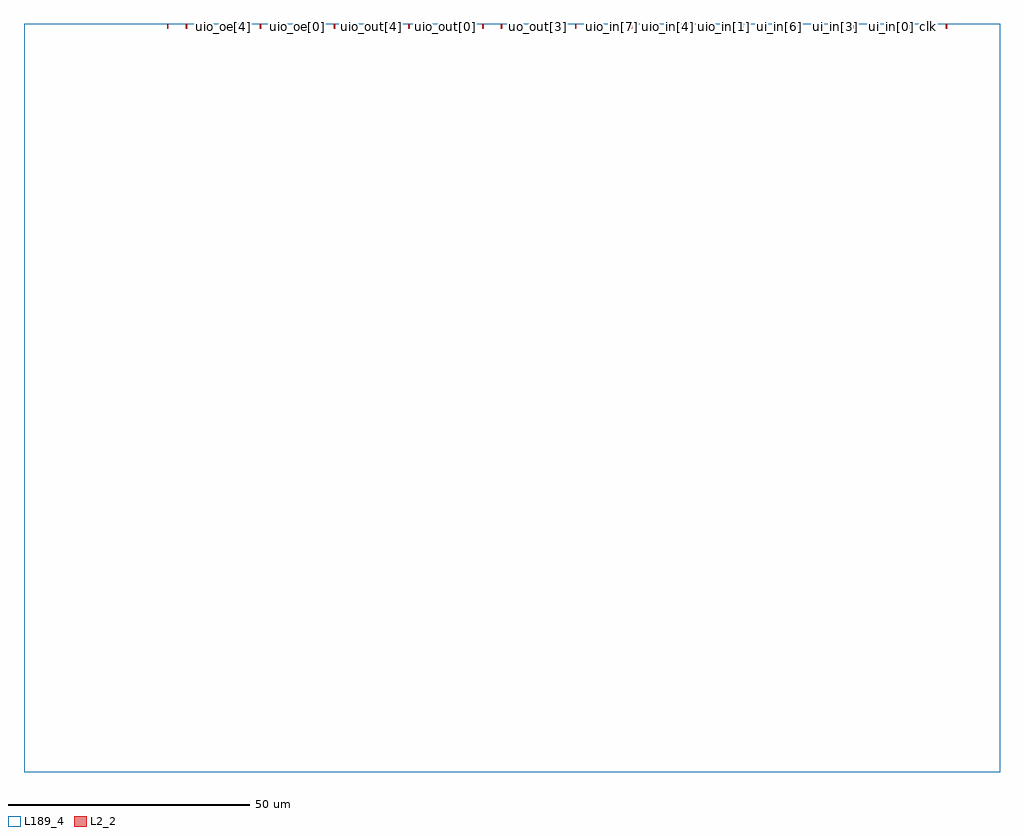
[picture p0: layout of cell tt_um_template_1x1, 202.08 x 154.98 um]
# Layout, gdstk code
import gdstk
lib = gdstk.Library(unit=1e-6, precision=1e-09)
def R(c, l, rs):  # rectangles x0, y0, x1, y1
    for r in rs: c.add(gdstk.rectangle(r[:2], r[2:], *l))
def A(c, l, x, y, w, h, nx, ny, dx, dy):  # array of equal rectangles
    R(c, l, [(x+i*dx, y+j*dy, x+i*dx+w, y+j*dy+h) for i in range(nx) for j in range(ny)])
L2_2 = (2, 2)
L189_4 = (189, 4)

tt_um_template_1x1 = lib.new_cell('tt_um_template_1x1')
A(tt_um_template_1x1, L2_2, 29.61, 153.98, 0.3, 1, 43, 1, 3.84, 0)
R(tt_um_template_1x1, L189_4, [(0,0,202.08,154.98)])
tt_um_template_1x1.add(gdstk.Label('clk', (187.2,154.48), layer=2, texttype=1))
tt_um_template_1x1.add(gdstk.Label('ena', (191.04,154.48), layer=2, texttype=1))
tt_um_template_1x1.add(gdstk.Label('rst_n', (183.36,154.48), layer=2, texttype=1))
tt_um_template_1x1.add(gdstk.Label('ui_in[0]', (179.52,154.48), layer=2, texttype=1))
tt_um_template_1x1.add(gdstk.Label('ui_in[1]', (175.68,154.48), layer=2, texttype=1))
tt_um_template_1x1.add(gdstk.Label('ui_in[2]', (171.84,154.48), layer=2, texttype=1))
tt_um_template_1x1.add(gdstk.Label('ui_in[3]', (168,154.48), layer=2, texttype=1))
tt_um_template_1x1.add(gdstk.Label('ui_in[4]', (164.16,154.48), layer=2, texttype=1))
tt_um_template_1x1.add(gdstk.Label('ui_in[5]', (160.32,154.48), layer=2, texttype=1))
tt_um_template_1x1.add(gdstk.Label('ui_in[6]', (156.48,154.48), layer=2, texttype=1))
tt_um_template_1x1.add(gdstk.Label('ui_in[7]', (152.64,154.48), layer=2, texttype=1))
tt_um_template_1x1.add(gdstk.Label('uio_in[0]', (148.8,154.48), layer=2, texttype=1))
tt_um_template_1x1.add(gdstk.Label('uio_in[1]', (144.96,154.48), layer=2, texttype=1))
tt_um_template_1x1.add(gdstk.Label('uio_in[2]', (141.12,154.48), layer=2, texttype=1))
tt_um_template_1x1.add(gdstk.Label('uio_in[3]', (137.28,154.48), layer=2, texttype=1))
tt_um_template_1x1.add(gdstk.Label('uio_in[4]', (133.44,154.48), layer=2, texttype=1))
tt_um_template_1x1.add(gdstk.Label('uio_in[5]', (129.6,154.48), layer=2, texttype=1))
tt_um_template_1x1.add(gdstk.Label('uio_in[6]', (125.76,154.48), layer=2, texttype=1))
tt_um_template_1x1.add(gdstk.Label('uio_in[7]', (121.92,154.48), layer=2, texttype=1))
tt_um_template_1x1.add(gdstk.Label('uio_oe[0]', (56.64,154.48), layer=2, texttype=1))
tt_um_template_1x1.add(gdstk.Label('uio_oe[1]', (52.8,154.48), layer=2, texttype=1))
tt_um_template_1x1.add(gdstk.Label('uio_oe[2]', (48.96,154.48), layer=2, texttype=1))
tt_um_template_1x1.add(gdstk.Label('uio_oe[3]', (45.12,154.48), layer=2, texttype=1))
tt_um_template_1x1.add(gdstk.Label('uio_oe[4]', (41.28,154.48), layer=2, texttype=1))
tt_um_template_1x1.add(gdstk.Label('uio_oe[5]', (37.44,154.48), layer=2, texttype=1))
tt_um_template_1x1.add(gdstk.Label('uio_oe[6]', (33.6,154.48), layer=2, texttype=1))
tt_um_template_1x1.add(gdstk.Label('uio_oe[7]', (29.76,154.48), layer=2, texttype=1))
tt_um_template_1x1.add(gdstk.Label('uio_out[0]', (87.36,154.48), layer=2, texttype=1))
tt_um_template_1x1.add(gdstk.Label('uio_out[1]', (83.52,154.48), layer=2, texttype=1))
tt_um_template_1x1.add(gdstk.Label('uio_out[2]', (79.68,154.48), layer=2, texttype=1))
tt_um_template_1x1.add(gdstk.Label('uio_out[3]', (75.84,154.48), layer=2, texttype=1))
tt_um_template_1x1.add(gdstk.Label('uio_out[4]', (72,154.48), layer=2, texttype=1))
tt_um_template_1x1.add(gdstk.Label('uio_out[5]', (68.16,154.48), layer=2, texttype=1))
tt_um_template_1x1.add(gdstk.Label('uio_out[6]', (64.32,154.48), layer=2, texttype=1))
tt_um_template_1x1.add(gdstk.Label('uio_out[7]', (60.48,154.48), layer=2, texttype=1))
tt_um_template_1x1.add(gdstk.Label('uo_out[0]', (118.08,154.48), layer=2, texttype=1))
tt_um_template_1x1.add(gdstk.Label('uo_out[1]', (114.24,154.48), layer=2, texttype=1))
tt_um_template_1x1.add(gdstk.Label('uo_out[2]', (110.4,154.48), layer=2, texttype=1))
tt_um_template_1x1.add(gdstk.Label('uo_out[3]', (106.56,154.48), layer=2, texttype=1))
tt_um_template_1x1.add(gdstk.Label('uo_out[4]', (102.72,154.48), layer=2, texttype=1))
tt_um_template_1x1.add(gdstk.Label('uo_out[5]', (98.88,154.48), layer=2, texttype=1))
tt_um_template_1x1.add(gdstk.Label('uo_out[6]', (95.04,154.48), layer=2, texttype=1))
tt_um_template_1x1.add(gdstk.Label('uo_out[7]', (91.2,154.48), layer=2, texttype=1))

lib.write_gds('tt_um_template_1x1.gds')
